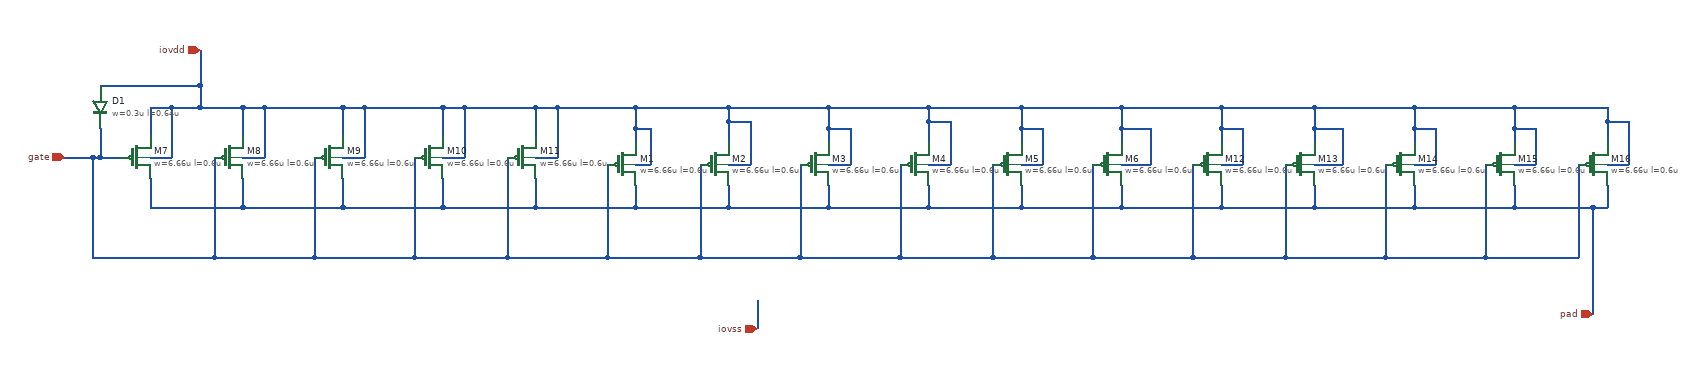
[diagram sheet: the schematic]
v {xschem version=3.4.4 file_version=1.2
}
G {}
K {}
V {}
S {}
E {}
N -130 -560 -130 -520 {
lab=pad}
N 1910 -550 1910 -520 {
lab=pad}
N 1780 -550 1780 -520 {
lab=pad}
N 1640 -520 1780 -520 {
lab=pad}
N 1640 -550 1640 -520 {
lab=pad}
N 1500 -520 1640 -520 {
lab=pad}
N 1500 -550 1500 -520 {
lab=pad}
N 1370 -520 1500 -520 {
lab=pad}
N 1370 -550 1370 -520 {
lab=pad}
N 1230 -520 1370 -520 {
lab=pad}
N 1230 -550 1230 -520 {
lab=pad}
N 1090 -520 1230 -520 {
lab=pad}
N 1090 -550 1090 -520 {
lab=pad}
N 960 -520 1090 -520 {
lab=pad}
N 960 -550 960 -520 {
lab=pad}
N 820 -520 960 -520 {
lab=pad}
N 820 -550 820 -520 {
lab=pad}
N 680 -520 820 -520 {
lab=pad}
N 680 -550 680 -520 {
lab=pad}
N 550 -520 680 -520 {
lab=pad}
N 550 -550 550 -520 {
lab=pad}
N 410 -520 550 -520 {
lab=pad}
N 410 -560 410 -520 {
lab=pad}
N 280 -520 410 -520 {
lab=pad}
N 280 -560 280 -520 {
lab=pad}
N 140 -520 280 -520 {
lab=pad}
N 140 -560 140 -520 {
lab=pad}
N 0 -520 140 -520 {
lab=pad}
N 0 -560 0 -520 {
lab=pad}
N -130 -520 0 -520 {
lab=pad}
N -130 -660 -130 -620 {
lab=iovdd}
N 1780 -660 1910 -660 {
lab=iovdd}
N 1910 -640 1910 -610 {
lab=iovdd}
N 0 -660 0 -620 {
lab=iovdd}
N -60 -660 0 -660 {
lab=iovdd}
N -130 -590 -100 -590 {
lab=iovdd}
N -100 -660 -100 -590 {
lab=iovdd}
N -130 -660 -100 -660 {
lab=iovdd}
N -0 -590 30 -590 {
lab=iovdd}
N 30 -660 30 -590 {
lab=iovdd}
N 0 -660 30 -660 {
lab=iovdd}
N 140 -660 140 -620 {
lab=iovdd}
N 30 -660 140 -660 {
lab=iovdd}
N 140 -590 170 -590 {
lab=iovdd}
N 170 -660 170 -590 {
lab=iovdd}
N 140 -660 170 -660 {
lab=iovdd}
N 280 -660 280 -620 {
lab=iovdd}
N 170 -660 280 -660 {
lab=iovdd}
N 280 -590 310 -590 {
lab=iovdd}
N 310 -660 310 -590 {
lab=iovdd}
N 280 -660 310 -660 {
lab=iovdd}
N 410 -660 410 -620 {
lab=iovdd}
N 310 -660 410 -660 {
lab=iovdd}
N 410 -590 440 -590 {
lab=iovdd}
N 440 -660 440 -590 {
lab=iovdd}
N 410 -660 440 -660 {
lab=iovdd}
N 550 -630 550 -610 {
lab=iovdd}
N 440 -660 550 -660 {
lab=iovdd}
N 550 -580 570 -580 {
lab=iovdd}
N 570 -630 570 -580 {
lab=iovdd}
N 550 -630 570 -630 {
lab=iovdd}
N 550 -660 550 -630 {
lab=iovdd}
N 680 -640 680 -610 {
lab=iovdd}
N 550 -660 680 -660 {
lab=iovdd}
N 680 -580 710 -580 {
lab=iovdd}
N 710 -640 710 -580 {
lab=iovdd}
N 680 -640 710 -640 {
lab=iovdd}
N 680 -660 680 -640 {
lab=iovdd}
N 820 -630 820 -610 {
lab=iovdd}
N 680 -660 820 -660 {
lab=iovdd}
N 820 -580 850 -580 {
lab=iovdd}
N 850 -630 850 -580 {
lab=iovdd}
N 820 -630 850 -630 {
lab=iovdd}
N 820 -660 820 -630 {
lab=iovdd}
N 960 -640 960 -610 {
lab=iovdd}
N 820 -660 960 -660 {
lab=iovdd}
N 960 -580 990 -580 {
lab=iovdd}
N 990 -640 990 -580 {
lab=iovdd}
N 960 -640 990 -640 {
lab=iovdd}
N 960 -660 960 -640 {
lab=iovdd}
N 1090 -630 1090 -610 {
lab=iovdd}
N 960 -660 1090 -660 {
lab=iovdd}
N 1090 -580 1120 -580 {
lab=iovdd}
N 1120 -630 1120 -580 {
lab=iovdd}
N 1090 -630 1120 -630 {
lab=iovdd}
N 1090 -660 1090 -630 {
lab=iovdd}
N 1230 -630 1230 -610 {
lab=iovdd}
N 1090 -660 1230 -660 {
lab=iovdd}
N 1230 -580 1270 -580 {
lab=iovdd}
N 1270 -630 1270 -580 {
lab=iovdd}
N 1230 -630 1270 -630 {
lab=iovdd}
N 1230 -660 1230 -630 {
lab=iovdd}
N 1370 -630 1370 -610 {
lab=iovdd}
N 1230 -660 1370 -660 {
lab=iovdd}
N 1370 -580 1400 -580 {
lab=iovdd}
N 1400 -630 1400 -580 {
lab=iovdd}
N 1370 -630 1400 -630 {
lab=iovdd}
N 1370 -660 1370 -630 {
lab=iovdd}
N 1500 -630 1500 -610 {
lab=iovdd}
N 1370 -660 1500 -660 {
lab=iovdd}
N 1500 -580 1540 -580 {
lab=iovdd}
N 1540 -630 1540 -580 {
lab=iovdd}
N 1500 -630 1540 -630 {
lab=iovdd}
N 1500 -660 1500 -630 {
lab=iovdd}
N 1640 -630 1640 -610 {
lab=iovdd}
N 1500 -660 1640 -660 {
lab=iovdd}
N 1640 -580 1670 -580 {
lab=iovdd}
N 1670 -630 1670 -580 {
lab=iovdd}
N 1640 -630 1670 -630 {
lab=iovdd}
N 1640 -660 1640 -630 {
lab=iovdd}
N 1780 -630 1780 -610 {
lab=iovdd}
N 1640 -660 1780 -660 {
lab=iovdd}
N 1780 -580 1810 -580 {
lab=iovdd}
N 1810 -630 1810 -580 {
lab=iovdd}
N 1780 -630 1810 -630 {
lab=iovdd}
N 1780 -660 1780 -630 {
lab=iovdd}
N 1910 -580 1940 -580 {
lab=iovdd}
N 1940 -640 1940 -580 {
lab=iovdd}
N 1910 -640 1940 -640 {
lab=iovdd}
N 1910 -660 1910 -640 {
lab=iovdd}
N -200 -590 -170 -590 {
lab=gate}
N -210 -590 -210 -450 {
lab=gate}
N -250 -590 -210 -590 {
lab=gate}
N 1740 -450 1870 -450 {
lab=gate}
N 1870 -580 1870 -450 {
lab=gate}
N -40 -590 -40 -450 {
lab=gate}
N -210 -450 -40 -450 {
lab=gate}
N 100 -590 100 -450 {
lab=gate}
N -40 -450 100 -450 {
lab=gate}
N 240 -590 240 -450 {
lab=gate}
N 100 -450 240 -450 {
lab=gate}
N 370 -590 370 -450 {
lab=gate}
N 240 -450 370 -450 {
lab=gate}
N 510 -580 510 -450 {
lab=gate}
N 370 -450 510 -450 {
lab=gate}
N 640 -580 640 -450 {
lab=gate}
N 510 -450 640 -450 {
lab=gate}
N 780 -580 780 -450 {
lab=gate}
N 640 -450 780 -450 {
lab=gate}
N 920 -580 920 -450 {
lab=gate}
N 780 -450 920 -450 {
lab=gate}
N 1050 -580 1050 -450 {
lab=gate}
N 920 -450 1050 -450 {
lab=gate}
N 1190 -580 1190 -450 {
lab=gate}
N 1050 -450 1190 -450 {
lab=gate}
N 1330 -580 1330 -450 {
lab=gate}
N 1190 -450 1330 -450 {
lab=gate}
N 1460 -580 1460 -450 {
lab=gate}
N 1330 -450 1460 -450 {
lab=gate}
N 1600 -580 1600 -450 {
lab=gate}
N 1460 -450 1600 -450 {
lab=gate}
N 1740 -580 1740 -450 {
lab=gate}
N 1600 -450 1740 -450 {
lab=gate}
N 1890 -520 1910 -520 {
lab=pad}
N 1890 -520 1890 -370 {
lab=pad}
N 1780 -520 1890 -520 {
lab=pad}
N -200 -630 -200 -590 {
lab=gate}
N -210 -590 -200 -590 {
lab=gate}
N -200 -690 -60 -690 {
lab=iovdd}
N -60 -690 -60 -660 {
lab=iovdd}
N -100 -660 -60 -660 {
lab=iovdd}
N -60 -740 -60 -690 {
lab=iovdd}
N 720 -390 720 -350 {
lab=pad}
C {sg13g2_pr/sg13_hv_pmos.sym} 530 -580 0 0 {name=M1
l=0.6u
w=6.66u
ng=1
m=1
model=sg13_hv_pmos
spiceprefix=X
}
C {sg13g2_pr/sg13_hv_pmos.sym} 660 -580 0 0 {name=M2
l=0.6u
w=6.66u
ng=1
m=1
model=sg13_hv_pmos
spiceprefix=X
}
C {sg13g2_pr/sg13_hv_pmos.sym} 800 -580 0 0 {name=M3
l=0.6u
w=6.66u
ng=1
m=1
model=sg13_hv_pmos
spiceprefix=X
}
C {sg13g2_pr/sg13_hv_pmos.sym} 940 -580 0 0 {name=M4
l=0.6u
w=6.66u
ng=1
m=1
model=sg13_hv_pmos
spiceprefix=X
}
C {sg13g2_pr/sg13_hv_pmos.sym} 1070 -580 0 0 {name=M5
l=0.6u
w=6.66u
ng=1
m=1
model=sg13_hv_pmos
spiceprefix=X
}
C {sg13g2_pr/sg13_hv_pmos.sym} 1210 -580 0 0 {name=M6
l=0.6u
w=6.66u
ng=1
m=1
model=sg13_hv_pmos
spiceprefix=X
}
C {sg13g2_pr/sg13_hv_pmos.sym} -150 -590 0 0 {name=M7
l=0.6u
w=6.66u
ng=1
m=1
model=sg13_hv_pmos
spiceprefix=X
}
C {sg13g2_pr/sg13_hv_pmos.sym} -20 -590 0 0 {name=M8
l=0.6u
w=6.66u
ng=1
m=1
model=sg13_hv_pmos
spiceprefix=X
}
C {sg13g2_pr/sg13_hv_pmos.sym} 120 -590 0 0 {name=M9
l=0.6u
w=6.66u
ng=1
m=1
model=sg13_hv_pmos
spiceprefix=X
}
C {sg13g2_pr/sg13_hv_pmos.sym} 260 -590 0 0 {name=M10
l=0.6u
w=6.66u
ng=1
m=1
model=sg13_hv_pmos
spiceprefix=X
}
C {sg13g2_pr/sg13_hv_pmos.sym} 390 -590 0 0 {name=M11
l=0.6u
w=6.66u
ng=1
m=1
model=sg13_hv_pmos
spiceprefix=X
}
C {sg13g2_pr/sg13_hv_pmos.sym} 1350 -580 0 0 {name=M12
l=0.6u
w=6.66u
ng=1
m=1
model=sg13_hv_pmos
spiceprefix=X
}
C {sg13g2_pr/sg13_hv_pmos.sym} 1480 -580 0 0 {name=M13
l=0.6u
w=6.66u
ng=1
m=1
model=sg13_hv_pmos
spiceprefix=X
}
C {sg13g2_pr/sg13_hv_pmos.sym} 1620 -580 0 0 {name=M14
l=0.6u
w=6.66u
ng=1
m=1
model=sg13_hv_pmos
spiceprefix=X
}
C {sg13g2_pr/sg13_hv_pmos.sym} 1760 -580 0 0 {name=M15
l=0.6u
w=6.66u
ng=1
m=1
model=sg13_hv_pmos
spiceprefix=X
}
C {sg13g2_pr/sg13_hv_pmos.sym} 1890 -580 0 0 {name=M16
l=0.6u
w=6.66u
ng=1
m=1
model=sg13_hv_pmos
spiceprefix=X
}
C {sg13g2_pr/dpantenna.sym} -200 -660 0 0 {name=D1
model=dpantenna
l=0.64u
w=0.3u
spiceprefix=X
}
C {devices/iopin.sym} -60 -740 3 0 {name=iovdd lab=iovdd}
C {devices/iopin.sym} -250 -590 2 0 {name=gate lab=gate}
C {devices/iopin.sym} 1890 -370 1 0 {name=pad lab=pad}
C {devices/iopin.sym} 720 -350 1 0 {name=iovss lab=iovss}
